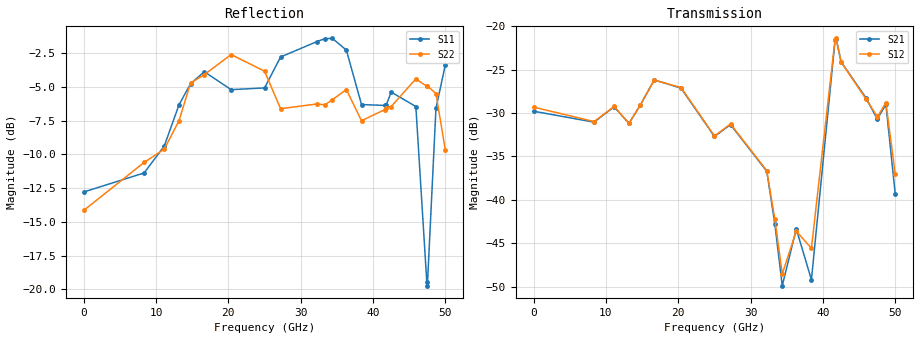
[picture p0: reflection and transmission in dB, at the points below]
!Keysight Technologies,N5245B,MY58422270,A.16.20.02
!Date: Thursday, March 05, 2026 01:41:35
!Correction: S11(C  2-Port  )
!S21(C  2-Port  )
!S12(C  2-Port  )
!S22(C  2-Port  )
!S2P File: Measurements: S11, S21, S12, S22:
# Hz S  dB  R 50
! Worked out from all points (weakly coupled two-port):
!   3201 points, 10 MHz to 50 GHz, reference 50 ohm
!   highest |S21| = -21.41 dB at 41.81 GHz (marker M1); lowest = -49.9 dB at 34.38 GHz (marker M2)
!   lowest |S11| = -19.7 dB at 47.52 GHz (marker M3), VSWR 1.23, Z = 45.4 + j8.73 ohm
!   |S11| at or under -10 dB: start of sweep to 10.05 GHz; 11.35 GHz to 11.94 GHz (587.5 MHz wide, 5.05 % of centre); 46.68 GHz to 48.24 GHz (1.559 GHz wide, 3.28 % of centre)
!   |S22| runs from -17.4 to -2.5 dB; largest |S21 - S12| = 0.0044
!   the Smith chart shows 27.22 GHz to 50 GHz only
!   S11 on the Smith chart (normalised r, x): 27.22 GHz: 0.18, +0.35; 32.24 GHz: 0.41, +1.81; 36.32 GHz: 2.51, -3.50; 42.52 GHz: 0.96, -1.25; 47.44 GHz: 0.86, +0.14; 50 GHz: 0.62, -1.41
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1e7  -12.79 -3.0  -29.79 1.0  -29.32 7.7  -14.15 37.9
8.352081e9  -11.38 175.1  -31.05 35.3  -30.98 35.3  -10.60 -171.9
1.113278e10  -9.39 106.8  -29.28 -60.6  -29.24 -61.1  -9.62 85.6
1.317924e10  -6.33 63.0  -31.20 -112.1  -31.18 -112.1  -7.51 -22.2
1.477267e10  -4.77 12.2  -29.07 -144.7  -29.04 -145.0  -4.72 -91.1
1.667854e10  -3.88 -43.9  -26.17 159.6  -26.20 160.0  -4.10 -142.2
2.038092e10  -5.21 -120.7  -27.13 41.9  -27.06 41.9  -2.61 153.9
2.5005e10  -5.08 -178.3  -32.70 -64.8  -32.64 -64.2  -3.84 71.2
2.722331e10  -2.79 140.4  -31.34 -114.1  -31.26 -113.5  -6.62 32.4
3.223793e10  -1.65 56.0  -36.71 48.7  -36.64 48.3  -6.27 -103.5
3.334708e10  -1.43 36.0  -42.77 1.5  -42.18 3.5  -6.33 -129.1
3.437812e10  -1.41 17.5  -49.90 -89.6  -48.54 -101.2  -5.96 -151.6
3.631524e10  -2.28 -21.7  -43.35 115.4  -43.61 117.5  -5.20 171.2
3.840857e10  -6.31 -22.7  -49.22 -128.1  -45.59 -108.7  -7.51 138.3
4.167354e10  -6.38 -53.0  -21.62 -54.9  -21.53 -54.6  -6.68 112.6
4.181414e10  -6.37 -53.0  -21.41 -68.1  -21.39 -67.7  -6.56 111.4
4.251712e10  -5.39 -59.1  -24.11 -117.4  -24.11 -118.2  -6.46 107.5
4.592269e10  -6.46 -115.9  -28.21 48.4  -28.35 47.2  -4.41 62.6
4.743801e10  -19.47 131.1  -30.57 -8.0  -30.31 -7.4  -4.96 43.7
4.751612e10  -19.73 112.7  -30.68 -8.6  -30.47 -8.1  -4.93 42.8
4.870338e10  -6.59 -21.0  -29.01 -85.3  -28.80 -83.3  -5.50 20.2
5e10  -3.37 -64.0  -39.32 -112.0  -37.04 -126.1  -9.69 5.9
